VERSION 5.7 ;
BUSBITCHARS "[]" ;
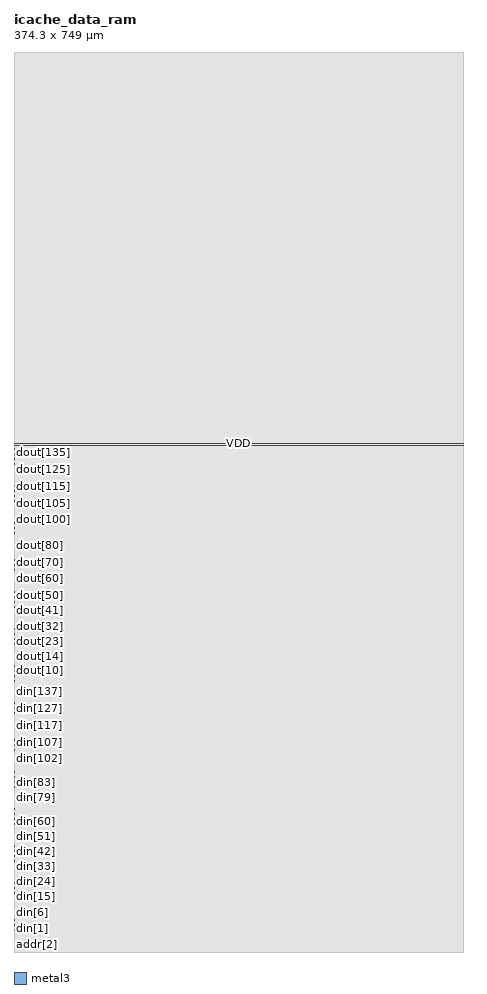
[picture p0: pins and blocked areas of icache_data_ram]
MACRO icache_data_ram
  FOREIGN icache_data_ram 0 0 ;
  SYMMETRY X Y R90 ;
  SIZE 374.300 BY 749.000 ;
  CLASS BLOCK ;
  PIN clk
    DIRECTION INPUT ;
    USE SIGNAL ;
    SHAPE ABUTMENT ;
    PORT
      LAYER metal3 ;
      RECT 0.000 1.400 0.140 1.540 ;
    END
  END clk
  PIN ce
    DIRECTION INPUT ;
    USE SIGNAL ;
    SHAPE ABUTMENT ;
    PORT
      LAYER metal3 ;
      RECT 0.000 2.800 0.140 2.940 ;
    END
  END ce
  PIN we
    DIRECTION INPUT ;
    USE SIGNAL ;
    SHAPE ABUTMENT ;
    PORT
      LAYER metal3 ;
      RECT 0.000 4.200 0.140 4.340 ;
    END
  END we
  PIN addr[0]
    DIRECTION INPUT ;
    USE SIGNAL ;
    SHAPE ABUTMENT ;
    PORT
      LAYER metal3 ;
      RECT 0.000 5.600 0.140 5.740 ;
    END
  END addr[0]
  PIN addr[1]
    DIRECTION INPUT ;
    USE SIGNAL ;
    SHAPE ABUTMENT ;
    PORT
      LAYER metal3 ;
      RECT 0.000 7.000 0.140 7.140 ;
    END
  END addr[1]
  PIN addr[2]
    DIRECTION INPUT ;
    USE SIGNAL ;
    SHAPE ABUTMENT ;
    PORT
      LAYER metal3 ;
      RECT 0.000 8.400 0.140 8.540 ;
    END
  END addr[2]
  PIN addr[3]
    DIRECTION INPUT ;
    USE SIGNAL ;
    SHAPE ABUTMENT ;
    PORT
      LAYER metal3 ;
      RECT 0.000 9.800 0.140 9.940 ;
    END
  END addr[3]
  PIN addr[4]
    DIRECTION INPUT ;
    USE SIGNAL ;
    SHAPE ABUTMENT ;
    PORT
      LAYER metal3 ;
      RECT 0.000 11.200 0.140 11.340 ;
    END
  END addr[4]
  PIN addr[5]
    DIRECTION INPUT ;
    USE SIGNAL ;
    SHAPE ABUTMENT ;
    PORT
      LAYER metal3 ;
      RECT 0.000 12.600 0.140 12.740 ;
    END
  END addr[5]
  PIN addr[6]
    DIRECTION INPUT ;
    USE SIGNAL ;
    SHAPE ABUTMENT ;
    PORT
      LAYER metal3 ;
      RECT 0.000 14.000 0.140 14.140 ;
    END
  END addr[6]
  PIN addr[7]
    DIRECTION INPUT ;
    USE SIGNAL ;
    SHAPE ABUTMENT ;
    PORT
      LAYER metal3 ;
      RECT 0.000 15.400 0.140 15.540 ;
    END
  END addr[7]
  PIN addr[8]
    DIRECTION INPUT ;
    USE SIGNAL ;
    SHAPE ABUTMENT ;
    PORT
      LAYER metal3 ;
      RECT 0.000 16.800 0.140 16.940 ;
    END
  END addr[8]
  PIN din[0]
    DIRECTION INPUT ;
    USE SIGNAL ;
    SHAPE ABUTMENT ;
    PORT
      LAYER metal3 ;
      RECT 0.000 18.200 0.140 18.340 ;
    END
  END din[0]
  PIN din[1]
    DIRECTION INPUT ;
    USE SIGNAL ;
    SHAPE ABUTMENT ;
    PORT
      LAYER metal3 ;
      RECT 0.000 19.600 0.140 19.740 ;
    END
  END din[1]
  PIN din[2]
    DIRECTION INPUT ;
    USE SIGNAL ;
    SHAPE ABUTMENT ;
    PORT
      LAYER metal3 ;
      RECT 0.000 21.000 0.140 21.140 ;
    END
  END din[2]
  PIN din[3]
    DIRECTION INPUT ;
    USE SIGNAL ;
    SHAPE ABUTMENT ;
    PORT
      LAYER metal3 ;
      RECT 0.000 22.400 0.140 22.540 ;
    END
  END din[3]
  PIN din[4]
    DIRECTION INPUT ;
    USE SIGNAL ;
    SHAPE ABUTMENT ;
    PORT
      LAYER metal3 ;
      RECT 0.000 23.800 0.140 23.940 ;
    END
  END din[4]
  PIN din[5]
    DIRECTION INPUT ;
    USE SIGNAL ;
    SHAPE ABUTMENT ;
    PORT
      LAYER metal3 ;
      RECT 0.000 25.200 0.140 25.340 ;
    END
  END din[5]
  PIN din[6]
    DIRECTION INPUT ;
    USE SIGNAL ;
    SHAPE ABUTMENT ;
    PORT
      LAYER metal3 ;
      RECT 0.000 26.600 0.140 26.740 ;
    END
  END din[6]
  PIN din[7]
    DIRECTION INPUT ;
    USE SIGNAL ;
    SHAPE ABUTMENT ;
    PORT
      LAYER metal3 ;
      RECT 0.000 28.000 0.140 28.140 ;
    END
  END din[7]
  PIN din[8]
    DIRECTION INPUT ;
    USE SIGNAL ;
    SHAPE ABUTMENT ;
    PORT
      LAYER metal3 ;
      RECT 0.000 29.400 0.140 29.540 ;
    END
  END din[8]
  PIN din[9]
    DIRECTION INPUT ;
    USE SIGNAL ;
    SHAPE ABUTMENT ;
    PORT
      LAYER metal3 ;
      RECT 0.000 30.800 0.140 30.940 ;
    END
  END din[9]
  PIN din[10]
    DIRECTION INPUT ;
    USE SIGNAL ;
    SHAPE ABUTMENT ;
    PORT
      LAYER metal3 ;
      RECT 0.000 32.200 0.140 32.340 ;
    END
  END din[10]
  PIN din[11]
    DIRECTION INPUT ;
    USE SIGNAL ;
    SHAPE ABUTMENT ;
    PORT
      LAYER metal3 ;
      RECT 0.000 33.600 0.140 33.740 ;
    END
  END din[11]
  PIN din[12]
    DIRECTION INPUT ;
    USE SIGNAL ;
    SHAPE ABUTMENT ;
    PORT
      LAYER metal3 ;
      RECT 0.000 35.000 0.140 35.140 ;
    END
  END din[12]
  PIN din[13]
    DIRECTION INPUT ;
    USE SIGNAL ;
    SHAPE ABUTMENT ;
    PORT
      LAYER metal3 ;
      RECT 0.000 36.400 0.140 36.540 ;
    END
  END din[13]
  PIN din[14]
    DIRECTION INPUT ;
    USE SIGNAL ;
    SHAPE ABUTMENT ;
    PORT
      LAYER metal3 ;
      RECT 0.000 37.800 0.140 37.940 ;
    END
  END din[14]
  PIN din[15]
    DIRECTION INPUT ;
    USE SIGNAL ;
    SHAPE ABUTMENT ;
    PORT
      LAYER metal3 ;
      RECT 0.000 39.200 0.140 39.340 ;
    END
  END din[15]
  PIN din[16]
    DIRECTION INPUT ;
    USE SIGNAL ;
    SHAPE ABUTMENT ;
    PORT
      LAYER metal3 ;
      RECT 0.000 40.600 0.140 40.740 ;
    END
  END din[16]
  PIN din[17]
    DIRECTION INPUT ;
    USE SIGNAL ;
    SHAPE ABUTMENT ;
    PORT
      LAYER metal3 ;
      RECT 0.000 42.000 0.140 42.140 ;
    END
  END din[17]
  PIN din[18]
    DIRECTION INPUT ;
    USE SIGNAL ;
    SHAPE ABUTMENT ;
    PORT
      LAYER metal3 ;
      RECT 0.000 43.400 0.140 43.540 ;
    END
  END din[18]
  PIN din[19]
    DIRECTION INPUT ;
    USE SIGNAL ;
    SHAPE ABUTMENT ;
    PORT
      LAYER metal3 ;
      RECT 0.000 44.800 0.140 44.940 ;
    END
  END din[19]
  PIN din[20]
    DIRECTION INPUT ;
    USE SIGNAL ;
    SHAPE ABUTMENT ;
    PORT
      LAYER metal3 ;
      RECT 0.000 46.200 0.140 46.340 ;
    END
  END din[20]
  PIN din[21]
    DIRECTION INPUT ;
    USE SIGNAL ;
    SHAPE ABUTMENT ;
    PORT
      LAYER metal3 ;
      RECT 0.000 47.600 0.140 47.740 ;
    END
  END din[21]
  PIN din[22]
    DIRECTION INPUT ;
    USE SIGNAL ;
    SHAPE ABUTMENT ;
    PORT
      LAYER metal3 ;
      RECT 0.000 49.000 0.140 49.140 ;
    END
  END din[22]
  PIN din[23]
    DIRECTION INPUT ;
    USE SIGNAL ;
    SHAPE ABUTMENT ;
    PORT
      LAYER metal3 ;
      RECT 0.000 50.400 0.140 50.540 ;
    END
  END din[23]
  PIN din[24]
    DIRECTION INPUT ;
    USE SIGNAL ;
    SHAPE ABUTMENT ;
    PORT
      LAYER metal3 ;
      RECT 0.000 51.800 0.140 51.940 ;
    END
  END din[24]
  PIN din[25]
    DIRECTION INPUT ;
    USE SIGNAL ;
    SHAPE ABUTMENT ;
    PORT
      LAYER metal3 ;
      RECT 0.000 53.200 0.140 53.340 ;
    END
  END din[25]
  PIN din[26]
    DIRECTION INPUT ;
    USE SIGNAL ;
    SHAPE ABUTMENT ;
    PORT
      LAYER metal3 ;
      RECT 0.000 54.600 0.140 54.740 ;
    END
  END din[26]
  PIN din[27]
    DIRECTION INPUT ;
    USE SIGNAL ;
    SHAPE ABUTMENT ;
    PORT
      LAYER metal3 ;
      RECT 0.000 56.000 0.140 56.140 ;
    END
  END din[27]
  PIN din[28]
    DIRECTION INPUT ;
    USE SIGNAL ;
    SHAPE ABUTMENT ;
    PORT
      LAYER metal3 ;
      RECT 0.000 57.400 0.140 57.540 ;
    END
  END din[28]
  PIN din[29]
    DIRECTION INPUT ;
    USE SIGNAL ;
    SHAPE ABUTMENT ;
    PORT
      LAYER metal3 ;
      RECT 0.000 58.800 0.140 58.940 ;
    END
  END din[29]
  PIN din[30]
    DIRECTION INPUT ;
    USE SIGNAL ;
    SHAPE ABUTMENT ;
    PORT
      LAYER metal3 ;
      RECT 0.000 60.200 0.140 60.340 ;
    END
  END din[30]
  PIN din[31]
    DIRECTION INPUT ;
    USE SIGNAL ;
    SHAPE ABUTMENT ;
    PORT
      LAYER metal3 ;
      RECT 0.000 61.600 0.140 61.740 ;
    END
  END din[31]
  PIN din[32]
    DIRECTION INPUT ;
    USE SIGNAL ;
    SHAPE ABUTMENT ;
    PORT
      LAYER metal3 ;
      RECT 0.000 63.000 0.140 63.140 ;
    END
  END din[32]
  PIN din[33]
    DIRECTION INPUT ;
    USE SIGNAL ;
    SHAPE ABUTMENT ;
    PORT
      LAYER metal3 ;
      RECT 0.000 64.400 0.140 64.540 ;
    END
  END din[33]
  PIN din[34]
    DIRECTION INPUT ;
    USE SIGNAL ;
    SHAPE ABUTMENT ;
    PORT
      LAYER metal3 ;
      RECT 0.000 65.800 0.140 65.940 ;
    END
  END din[34]
  PIN din[35]
    DIRECTION INPUT ;
    USE SIGNAL ;
    SHAPE ABUTMENT ;
    PORT
      LAYER metal3 ;
      RECT 0.000 67.200 0.140 67.340 ;
    END
  END din[35]
  PIN din[36]
    DIRECTION INPUT ;
    USE SIGNAL ;
    SHAPE ABUTMENT ;
    PORT
      LAYER metal3 ;
      RECT 0.000 68.600 0.140 68.740 ;
    END
  END din[36]
  PIN din[37]
    DIRECTION INPUT ;
    USE SIGNAL ;
    SHAPE ABUTMENT ;
    PORT
      LAYER metal3 ;
      RECT 0.000 70.000 0.140 70.140 ;
    END
  END din[37]
  PIN din[38]
    DIRECTION INPUT ;
    USE SIGNAL ;
    SHAPE ABUTMENT ;
    PORT
      LAYER metal3 ;
      RECT 0.000 71.400 0.140 71.540 ;
    END
  END din[38]
  PIN din[39]
    DIRECTION INPUT ;
    USE SIGNAL ;
    SHAPE ABUTMENT ;
    PORT
      LAYER metal3 ;
      RECT 0.000 72.800 0.140 72.940 ;
    END
  END din[39]
  PIN din[40]
    DIRECTION INPUT ;
    USE SIGNAL ;
    SHAPE ABUTMENT ;
    PORT
      LAYER metal3 ;
      RECT 0.000 74.200 0.140 74.340 ;
    END
  END din[40]
  PIN din[41]
    DIRECTION INPUT ;
    USE SIGNAL ;
    SHAPE ABUTMENT ;
    PORT
      LAYER metal3 ;
      RECT 0.000 75.600 0.140 75.740 ;
    END
  END din[41]
  PIN din[42]
    DIRECTION INPUT ;
    USE SIGNAL ;
    SHAPE ABUTMENT ;
    PORT
      LAYER metal3 ;
      RECT 0.000 77.000 0.140 77.140 ;
    END
  END din[42]
  PIN din[43]
    DIRECTION INPUT ;
    USE SIGNAL ;
    SHAPE ABUTMENT ;
    PORT
      LAYER metal3 ;
      RECT 0.000 78.400 0.140 78.540 ;
    END
  END din[43]
  PIN din[44]
    DIRECTION INPUT ;
    USE SIGNAL ;
    SHAPE ABUTMENT ;
    PORT
      LAYER metal3 ;
      RECT 0.000 79.800 0.140 79.940 ;
    END
  END din[44]
  PIN din[45]
    DIRECTION INPUT ;
    USE SIGNAL ;
    SHAPE ABUTMENT ;
    PORT
      LAYER metal3 ;
      RECT 0.000 81.200 0.140 81.340 ;
    END
  END din[45]
  PIN din[46]
    DIRECTION INPUT ;
    USE SIGNAL ;
    SHAPE ABUTMENT ;
    PORT
      LAYER metal3 ;
      RECT 0.000 82.600 0.140 82.740 ;
    END
  END din[46]
  PIN din[47]
    DIRECTION INPUT ;
    USE SIGNAL ;
    SHAPE ABUTMENT ;
    PORT
      LAYER metal3 ;
      RECT 0.000 84.000 0.140 84.140 ;
    END
  END din[47]
  PIN din[48]
    DIRECTION INPUT ;
    USE SIGNAL ;
    SHAPE ABUTMENT ;
    PORT
      LAYER metal3 ;
      RECT 0.000 85.400 0.140 85.540 ;
    END
  END din[48]
  PIN din[49]
    DIRECTION INPUT ;
    USE SIGNAL ;
    SHAPE ABUTMENT ;
    PORT
      LAYER metal3 ;
      RECT 0.000 86.800 0.140 86.940 ;
    END
  END din[49]
  PIN din[50]
    DIRECTION INPUT ;
    USE SIGNAL ;
    SHAPE ABUTMENT ;
    PORT
      LAYER metal3 ;
      RECT 0.000 88.200 0.140 88.340 ;
    END
  END din[50]
  PIN din[51]
    DIRECTION INPUT ;
    USE SIGNAL ;
    SHAPE ABUTMENT ;
    PORT
      LAYER metal3 ;
      RECT 0.000 89.600 0.140 89.740 ;
    END
  END din[51]
  PIN din[52]
    DIRECTION INPUT ;
    USE SIGNAL ;
    SHAPE ABUTMENT ;
    PORT
      LAYER metal3 ;
      RECT 0.000 91.000 0.140 91.140 ;
    END
  END din[52]
  PIN din[53]
    DIRECTION INPUT ;
    USE SIGNAL ;
    SHAPE ABUTMENT ;
    PORT
      LAYER metal3 ;
      RECT 0.000 92.400 0.140 92.540 ;
    END
  END din[53]
  PIN din[54]
    DIRECTION INPUT ;
    USE SIGNAL ;
    SHAPE ABUTMENT ;
    PORT
      LAYER metal3 ;
      RECT 0.000 93.800 0.140 93.940 ;
    END
  END din[54]
  PIN din[55]
    DIRECTION INPUT ;
    USE SIGNAL ;
    SHAPE ABUTMENT ;
    PORT
      LAYER metal3 ;
      RECT 0.000 95.200 0.140 95.340 ;
    END
  END din[55]
  PIN din[56]
    DIRECTION INPUT ;
    USE SIGNAL ;
    SHAPE ABUTMENT ;
    PORT
      LAYER metal3 ;
      RECT 0.000 96.600 0.140 96.740 ;
    END
  END din[56]
  PIN din[57]
    DIRECTION INPUT ;
    USE SIGNAL ;
    SHAPE ABUTMENT ;
    PORT
      LAYER metal3 ;
      RECT 0.000 98.000 0.140 98.140 ;
    END
  END din[57]
  PIN din[58]
    DIRECTION INPUT ;
    USE SIGNAL ;
    SHAPE ABUTMENT ;
    PORT
      LAYER metal3 ;
      RECT 0.000 99.400 0.140 99.540 ;
    END
  END din[58]
  PIN din[59]
    DIRECTION INPUT ;
    USE SIGNAL ;
    SHAPE ABUTMENT ;
    PORT
      LAYER metal3 ;
      RECT 0.000 100.800 0.140 100.940 ;
    END
  END din[59]
  PIN din[60]
    DIRECTION INPUT ;
    USE SIGNAL ;
    SHAPE ABUTMENT ;
    PORT
      LAYER metal3 ;
      RECT 0.000 102.200 0.140 102.340 ;
    END
  END din[60]
  PIN din[61]
    DIRECTION INPUT ;
    USE SIGNAL ;
    SHAPE ABUTMENT ;
    PORT
      LAYER metal3 ;
      RECT 0.000 103.600 0.140 103.740 ;
    END
  END din[61]
  PIN din[62]
    DIRECTION INPUT ;
    USE SIGNAL ;
    SHAPE ABUTMENT ;
    PORT
      LAYER metal3 ;
      RECT 0.000 105.000 0.140 105.140 ;
    END
  END din[62]
  PIN din[63]
    DIRECTION INPUT ;
    USE SIGNAL ;
    SHAPE ABUTMENT ;
    PORT
      LAYER metal3 ;
      RECT 0.000 106.400 0.140 106.540 ;
    END
  END din[63]
  PIN din[64]
    DIRECTION INPUT ;
    USE SIGNAL ;
    SHAPE ABUTMENT ;
    PORT
      LAYER metal3 ;
      RECT 0.000 107.800 0.140 107.940 ;
    END
  END din[64]
  PIN din[65]
    DIRECTION INPUT ;
    USE SIGNAL ;
    SHAPE ABUTMENT ;
    PORT
      LAYER metal3 ;
      RECT 0.000 109.200 0.140 109.340 ;
    END
  END din[65]
  PIN din[66]
    DIRECTION INPUT ;
    USE SIGNAL ;
    SHAPE ABUTMENT ;
    PORT
      LAYER metal3 ;
      RECT 0.000 110.600 0.140 110.740 ;
    END
  END din[66]
  PIN din[67]
    DIRECTION INPUT ;
    USE SIGNAL ;
    SHAPE ABUTMENT ;
    PORT
      LAYER metal3 ;
      RECT 0.000 112.000 0.140 112.140 ;
    END
  END din[67]
  PIN din[68]
    DIRECTION INPUT ;
    USE SIGNAL ;
    SHAPE ABUTMENT ;
    PORT
      LAYER metal3 ;
      RECT 0.000 113.400 0.140 113.540 ;
    END
  END din[68]
  PIN din[69]
    DIRECTION INPUT ;
    USE SIGNAL ;
    SHAPE ABUTMENT ;
    PORT
      LAYER metal3 ;
      RECT 0.000 114.800 0.140 114.940 ;
    END
  END din[69]
  PIN din[70]
    DIRECTION INPUT ;
    USE SIGNAL ;
    SHAPE ABUTMENT ;
    PORT
      LAYER metal3 ;
      RECT 0.000 116.200 0.140 116.340 ;
    END
  END din[70]
  PIN din[71]
    DIRECTION INPUT ;
    USE SIGNAL ;
    SHAPE ABUTMENT ;
    PORT
      LAYER metal3 ;
      RECT 0.000 117.600 0.140 117.740 ;
    END
  END din[71]
  PIN din[72]
    DIRECTION INPUT ;
    USE SIGNAL ;
    SHAPE ABUTMENT ;
    PORT
      LAYER metal3 ;
      RECT 0.000 119.000 0.140 119.140 ;
    END
  END din[72]
  PIN din[73]
    DIRECTION INPUT ;
    USE SIGNAL ;
    SHAPE ABUTMENT ;
    PORT
      LAYER metal3 ;
      RECT 0.000 120.400 0.140 120.540 ;
    END
  END din[73]
  PIN din[74]
    DIRECTION INPUT ;
    USE SIGNAL ;
    SHAPE ABUTMENT ;
    PORT
      LAYER metal3 ;
      RECT 0.000 121.800 0.140 121.940 ;
    END
  END din[74]
  PIN din[75]
    DIRECTION INPUT ;
    USE SIGNAL ;
    SHAPE ABUTMENT ;
    PORT
      LAYER metal3 ;
      RECT 0.000 123.200 0.140 123.340 ;
    END
  END din[75]
  PIN din[76]
    DIRECTION INPUT ;
    USE SIGNAL ;
    SHAPE ABUTMENT ;
    PORT
      LAYER metal3 ;
      RECT 0.000 124.600 0.140 124.740 ;
    END
  END din[76]
  PIN din[77]
    DIRECTION INPUT ;
    USE SIGNAL ;
    SHAPE ABUTMENT ;
    PORT
      LAYER metal3 ;
      RECT 0.000 126.000 0.140 126.140 ;
    END
  END din[77]
  PIN din[78]
    DIRECTION INPUT ;
    USE SIGNAL ;
    SHAPE ABUTMENT ;
    PORT
      LAYER metal3 ;
      RECT 0.000 127.400 0.140 127.540 ;
    END
  END din[78]
  PIN din[79]
    DIRECTION INPUT ;
    USE SIGNAL ;
    SHAPE ABUTMENT ;
    PORT
      LAYER metal3 ;
      RECT 0.000 128.800 0.140 128.940 ;
    END
  END din[79]
  PIN din[80]
    DIRECTION INPUT ;
    USE SIGNAL ;
    SHAPE ABUTMENT ;
    PORT
      LAYER metal3 ;
      RECT 0.000 130.200 0.140 130.340 ;
    END
  END din[80]
  PIN din[81]
    DIRECTION INPUT ;
    USE SIGNAL ;
    SHAPE ABUTMENT ;
    PORT
      LAYER metal3 ;
      RECT 0.000 131.600 0.140 131.740 ;
    END
  END din[81]
  PIN din[82]
    DIRECTION INPUT ;
    USE SIGNAL ;
    SHAPE ABUTMENT ;
    PORT
      LAYER metal3 ;
      RECT 0.000 133.000 0.140 133.140 ;
    END
  END din[82]
  PIN din[83]
    DIRECTION INPUT ;
    USE SIGNAL ;
    SHAPE ABUTMENT ;
    PORT
      LAYER metal3 ;
      RECT 0.000 134.400 0.140 134.540 ;
    END
  END din[83]
  PIN din[84]
    DIRECTION INPUT ;
    USE SIGNAL ;
    SHAPE ABUTMENT ;
    PORT
      LAYER metal3 ;
      RECT 0.000 135.800 0.140 135.940 ;
    END
  END din[84]
  PIN din[85]
    DIRECTION INPUT ;
    USE SIGNAL ;
    SHAPE ABUTMENT ;
    PORT
      LAYER metal3 ;
      RECT 0.000 137.200 0.140 137.340 ;
    END
  END din[85]
  PIN din[86]
    DIRECTION INPUT ;
    USE SIGNAL ;
    SHAPE ABUTMENT ;
    PORT
      LAYER metal3 ;
      RECT 0.000 138.600 0.140 138.740 ;
    END
  END din[86]
  PIN din[87]
    DIRECTION INPUT ;
    USE SIGNAL ;
    SHAPE ABUTMENT ;
    PORT
      LAYER metal3 ;
      RECT 0.000 140.000 0.140 140.140 ;
    END
  END din[87]
  PIN din[88]
    DIRECTION INPUT ;
    USE SIGNAL ;
    SHAPE ABUTMENT ;
    PORT
      LAYER metal3 ;
      RECT 0.000 141.400 0.140 141.540 ;
    END
  END din[88]
  PIN din[89]
    DIRECTION INPUT ;
    USE SIGNAL ;
    SHAPE ABUTMENT ;
    PORT
      LAYER metal3 ;
      RECT 0.000 142.800 0.140 142.940 ;
    END
  END din[89]
  PIN din[90]
    DIRECTION INPUT ;
    USE SIGNAL ;
    SHAPE ABUTMENT ;
    PORT
      LAYER metal3 ;
      RECT 0.000 144.200 0.140 144.340 ;
    END
  END din[90]
  PIN din[91]
    DIRECTION INPUT ;
    USE SIGNAL ;
    SHAPE ABUTMENT ;
    PORT
      LAYER metal3 ;
      RECT 0.000 145.600 0.140 145.740 ;
    END
  END din[91]
  PIN din[92]
    DIRECTION INPUT ;
    USE SIGNAL ;
    SHAPE ABUTMENT ;
    PORT
      LAYER metal3 ;
      RECT 0.000 147.000 0.140 147.140 ;
    END
  END din[92]
  PIN din[93]
    DIRECTION INPUT ;
    USE SIGNAL ;
    SHAPE ABUTMENT ;
    PORT
      LAYER metal3 ;
      RECT 0.000 148.400 0.140 148.540 ;
    END
  END din[93]
  PIN din[94]
    DIRECTION INPUT ;
    USE SIGNAL ;
    SHAPE ABUTMENT ;
    PORT
      LAYER metal3 ;
      RECT 0.000 149.800 0.140 149.940 ;
    END
  END din[94]
  PIN din[95]
    DIRECTION INPUT ;
    USE SIGNAL ;
    SHAPE ABUTMENT ;
    PORT
      LAYER metal3 ;
      RECT 0.000 151.200 0.140 151.340 ;
    END
  END din[95]
  PIN din[96]
    DIRECTION INPUT ;
    USE SIGNAL ;
    SHAPE ABUTMENT ;
    PORT
      LAYER metal3 ;
      RECT 0.000 152.600 0.140 152.740 ;
    END
  END din[96]
  PIN din[97]
    DIRECTION INPUT ;
    USE SIGNAL ;
    SHAPE ABUTMENT ;
    PORT
      LAYER metal3 ;
      RECT 0.000 154.000 0.140 154.140 ;
    END
  END din[97]
  PIN din[98]
    DIRECTION INPUT ;
    USE SIGNAL ;
    SHAPE ABUTMENT ;
    PORT
      LAYER metal3 ;
      RECT 0.000 155.400 0.140 155.540 ;
    END
  END din[98]
  PIN din[99]
    DIRECTION INPUT ;
    USE SIGNAL ;
    SHAPE ABUTMENT ;
    PORT
      LAYER metal3 ;
      RECT 0.000 156.800 0.140 156.940 ;
    END
  END din[99]
  PIN din[100]
    DIRECTION INPUT ;
    USE SIGNAL ;
    SHAPE ABUTMENT ;
    PORT
      LAYER metal3 ;
      RECT 0.000 158.200 0.140 158.340 ;
    END
  END din[100]
  PIN din[101]
    DIRECTION INPUT ;
    USE SIGNAL ;
    SHAPE ABUTMENT ;
    PORT
      LAYER metal3 ;
      RECT 0.000 159.600 0.140 159.740 ;
    END
  END din[101]
  PIN din[102]
    DIRECTION INPUT ;
    USE SIGNAL ;
    SHAPE ABUTMENT ;
    PORT
      LAYER metal3 ;
      RECT 0.000 161.000 0.140 161.140 ;
    END
  END din[102]
  PIN din[103]
    DIRECTION INPUT ;
    USE SIGNAL ;
    SHAPE ABUTMENT ;
    PORT
      LAYER metal3 ;
      RECT 0.000 162.400 0.140 162.540 ;
    END
  END din[103]
  PIN din[104]
    DIRECTION INPUT ;
    USE SIGNAL ;
    SHAPE ABUTMENT ;
    PORT
      LAYER metal3 ;
      RECT 0.000 163.800 0.140 163.940 ;
    END
  END din[104]
  PIN din[105]
    DIRECTION INPUT ;
    USE SIGNAL ;
    SHAPE ABUTMENT ;
    PORT
      LAYER metal3 ;
      RECT 0.000 165.200 0.140 165.340 ;
    END
  END din[105]
  PIN din[106]
    DIRECTION INPUT ;
    USE SIGNAL ;
    SHAPE ABUTMENT ;
    PORT
      LAYER metal3 ;
      RECT 0.000 166.600 0.140 166.740 ;
    END
  END din[106]
  PIN din[107]
    DIRECTION INPUT ;
    USE SIGNAL ;
    SHAPE ABUTMENT ;
    PORT
      LAYER metal3 ;
      RECT 0.000 168.000 0.140 168.140 ;
    END
  END din[107]
  PIN din[108]
    DIRECTION INPUT ;
    USE SIGNAL ;
    SHAPE ABUTMENT ;
    PORT
      LAYER metal3 ;
      RECT 0.000 169.400 0.140 169.540 ;
    END
  END din[108]
  PIN din[109]
    DIRECTION INPUT ;
    USE SIGNAL ;
    SHAPE ABUTMENT ;
    PORT
      LAYER metal3 ;
      RECT 0.000 170.800 0.140 170.940 ;
    END
  END din[109]
  PIN din[110]
    DIRECTION INPUT ;
    USE SIGNAL ;
    SHAPE ABUTMENT ;
    PORT
      LAYER metal3 ;
      RECT 0.000 172.200 0.140 172.340 ;
    END
  END din[110]
  PIN din[111]
    DIRECTION INPUT ;
    USE SIGNAL ;
    SHAPE ABUTMENT ;
    PORT
      LAYER metal3 ;
      RECT 0.000 173.600 0.140 173.740 ;
    END
  END din[111]
  PIN din[112]
    DIRECTION INPUT ;
    USE SIGNAL ;
    SHAPE ABUTMENT ;
    PORT
      LAYER metal3 ;
      RECT 0.000 175.000 0.140 175.140 ;
    END
  END din[112]
  PIN din[113]
    DIRECTION INPUT ;
    USE SIGNAL ;
    SHAPE ABUTMENT ;
    PORT
      LAYER metal3 ;
      RECT 0.000 176.400 0.140 176.540 ;
    END
  END din[113]
  PIN din[114]
    DIRECTION INPUT ;
    USE SIGNAL ;
    SHAPE ABUTMENT ;
    PORT
      LAYER metal3 ;
      RECT 0.000 177.800 0.140 177.940 ;
    END
  END din[114]
  PIN din[115]
    DIRECTION INPUT ;
    USE SIGNAL ;
    SHAPE ABUTMENT ;
    PORT
      LAYER metal3 ;
      RECT 0.000 179.200 0.140 179.340 ;
    END
  END din[115]
  PIN din[116]
    DIRECTION INPUT ;
    USE SIGNAL ;
    SHAPE ABUTMENT ;
    PORT
      LAYER metal3 ;
      RECT 0.000 180.600 0.140 180.740 ;
    END
  END din[116]
  PIN din[117]
    DIRECTION INPUT ;
    USE SIGNAL ;
    SHAPE ABUTMENT ;
    PORT
      LAYER metal3 ;
      RECT 0.000 182.000 0.140 182.140 ;
    END
  END din[117]
  PIN din[118]
    DIRECTION INPUT ;
    USE SIGNAL ;
    SHAPE ABUTMENT ;
    PORT
      LAYER metal3 ;
      RECT 0.000 183.400 0.140 183.540 ;
    END
  END din[118]
  PIN din[119]
    DIRECTION INPUT ;
    USE SIGNAL ;
    SHAPE ABUTMENT ;
    PORT
      LAYER metal3 ;
      RECT 0.000 184.800 0.140 184.940 ;
    END
  END din[119]
  PIN din[120]
    DIRECTION INPUT ;
    USE SIGNAL ;
    SHAPE ABUTMENT ;
    PORT
      LAYER metal3 ;
      RECT 0.000 186.200 0.140 186.340 ;
    END
  END din[120]
  PIN din[121]
    DIRECTION INPUT ;
    USE SIGNAL ;
    SHAPE ABUTMENT ;
    PORT
      LAYER metal3 ;
      RECT 0.000 187.600 0.140 187.740 ;
    END
  END din[121]
  PIN din[122]
    DIRECTION INPUT ;
    USE SIGNAL ;
    SHAPE ABUTMENT ;
    PORT
      LAYER metal3 ;
      RECT 0.000 189.000 0.140 189.140 ;
    END
  END din[122]
  PIN din[123]
    DIRECTION INPUT ;
    USE SIGNAL ;
    SHAPE ABUTMENT ;
    PORT
      LAYER metal3 ;
      RECT 0.000 190.400 0.140 190.540 ;
    END
  END din[123]
  PIN din[124]
    DIRECTION INPUT ;
    USE SIGNAL ;
    SHAPE ABUTMENT ;
    PORT
      LAYER metal3 ;
      RECT 0.000 191.800 0.140 191.940 ;
    END
  END din[124]
  PIN din[125]
    DIRECTION INPUT ;
    USE SIGNAL ;
    SHAPE ABUTMENT ;
    PORT
      LAYER metal3 ;
      RECT 0.000 193.200 0.140 193.340 ;
    END
  END din[125]
  PIN din[126]
    DIRECTION INPUT ;
    USE SIGNAL ;
    SHAPE ABUTMENT ;
    PORT
      LAYER metal3 ;
      RECT 0.000 194.600 0.140 194.740 ;
    END
  END din[126]
  PIN din[127]
    DIRECTION INPUT ;
    USE SIGNAL ;
    SHAPE ABUTMENT ;
    PORT
      LAYER metal3 ;
      RECT 0.000 196.000 0.140 196.140 ;
    END
  END din[127]
  PIN din[128]
    DIRECTION INPUT ;
    USE SIGNAL ;
    SHAPE ABUTMENT ;
    PORT
      LAYER metal3 ;
      RECT 0.000 197.400 0.140 197.540 ;
    END
  END din[128]
  PIN din[129]
    DIRECTION INPUT ;
    USE SIGNAL ;
    SHAPE ABUTMENT ;
    PORT
      LAYER metal3 ;
      RECT 0.000 198.800 0.140 198.940 ;
    END
  END din[129]
  PIN din[130]
    DIRECTION INPUT ;
    USE SIGNAL ;
    SHAPE ABUTMENT ;
    PORT
      LAYER metal3 ;
      RECT 0.000 200.200 0.140 200.340 ;
    END
  END din[130]
  PIN din[131]
    DIRECTION INPUT ;
    USE SIGNAL ;
    SHAPE ABUTMENT ;
    PORT
      LAYER metal3 ;
      RECT 0.000 201.600 0.140 201.740 ;
    END
  END din[131]
  PIN din[132]
    DIRECTION INPUT ;
    USE SIGNAL ;
    SHAPE ABUTMENT ;
    PORT
      LAYER metal3 ;
      RECT 0.000 203.000 0.140 203.140 ;
    END
  END din[132]
  PIN din[133]
    DIRECTION INPUT ;
    USE SIGNAL ;
    SHAPE ABUTMENT ;
    PORT
      LAYER metal3 ;
      RECT 0.000 204.400 0.140 204.540 ;
    END
  END din[133]
  PIN din[134]
    DIRECTION INPUT ;
    USE SIGNAL ;
    SHAPE ABUTMENT ;
    PORT
      LAYER metal3 ;
      RECT 0.000 205.800 0.140 205.940 ;
    END
  END din[134]
  PIN din[135]
    DIRECTION INPUT ;
    USE SIGNAL ;
    SHAPE ABUTMENT ;
    PORT
      LAYER metal3 ;
      RECT 0.000 207.200 0.140 207.340 ;
    END
  END din[135]
  PIN din[136]
    DIRECTION INPUT ;
    USE SIGNAL ;
    SHAPE ABUTMENT ;
    PORT
      LAYER metal3 ;
      RECT 0.000 208.600 0.140 208.740 ;
    END
  END din[136]
  PIN din[137]
    DIRECTION INPUT ;
    USE SIGNAL ;
    SHAPE ABUTMENT ;
    PORT
      LAYER metal3 ;
      RECT 0.000 210.000 0.140 210.140 ;
    END
  END din[137]
  PIN din[138]
    DIRECTION INPUT ;
    USE SIGNAL ;
    SHAPE ABUTMENT ;
    PORT
      LAYER metal3 ;
      RECT 0.000 211.400 0.140 211.540 ;
    END
  END din[138]
  PIN din[139]
    DIRECTION INPUT ;
    USE SIGNAL ;
    SHAPE ABUTMENT ;
    PORT
      LAYER metal3 ;
      RECT 0.000 212.800 0.140 212.940 ;
    END
  END din[139]
  PIN din[140]
    DIRECTION INPUT ;
    USE SIGNAL ;
    SHAPE ABUTMENT ;
    PORT
      LAYER metal3 ;
      RECT 0.000 214.200 0.140 214.340 ;
    END
  END din[140]
  PIN din[141]
    DIRECTION INPUT ;
    USE SIGNAL ;
    SHAPE ABUTMENT ;
    PORT
      LAYER metal3 ;
      RECT 0.000 215.600 0.140 215.740 ;
    END
  END din[141]
  PIN din[142]
    DIRECTION INPUT ;
    USE SIGNAL ;
    SHAPE ABUTMENT ;
    PORT
      LAYER metal3 ;
      RECT 0.000 217.000 0.140 217.140 ;
    END
  END din[142]
  PIN din[143]
    DIRECTION INPUT ;
    USE SIGNAL ;
    SHAPE ABUTMENT ;
    PORT
      LAYER metal3 ;
      RECT 0.000 218.400 0.140 218.540 ;
    END
  END din[143]
  PIN dout[0]
    DIRECTION OUTPUT ;
    USE SIGNAL ;
    SHAPE ABUTMENT ;
    PORT
      LAYER metal3 ;
      RECT 0.000 219.800 0.140 219.940 ;
    END
  END dout[0]
  PIN dout[1]
    DIRECTION OUTPUT ;
    USE SIGNAL ;
    SHAPE ABUTMENT ;
    PORT
      LAYER metal3 ;
      RECT 0.000 221.200 0.140 221.340 ;
    END
  END dout[1]
  PIN dout[2]
    DIRECTION OUTPUT ;
    USE SIGNAL ;
    SHAPE ABUTMENT ;
    PORT
      LAYER metal3 ;
      RECT 0.000 222.600 0.140 222.740 ;
    END
  END dout[2]
  PIN dout[3]
    DIRECTION OUTPUT ;
    USE SIGNAL ;
    SHAPE ABUTMENT ;
    PORT
      LAYER metal3 ;
      RECT 0.000 224.000 0.140 224.140 ;
    END
  END dout[3]
  PIN dout[4]
    DIRECTION OUTPUT ;
    USE SIGNAL ;
    SHAPE ABUTMENT ;
    PORT
      LAYER metal3 ;
      RECT 0.000 225.400 0.140 225.540 ;
    END
  END dout[4]
  PIN dout[5]
    DIRECTION OUTPUT ;
    USE SIGNAL ;
    SHAPE ABUTMENT ;
    PORT
      LAYER metal3 ;
      RECT 0.000 226.800 0.140 226.940 ;
    END
  END dout[5]
  PIN dout[6]
    DIRECTION OUTPUT ;
    USE SIGNAL ;
    SHAPE ABUTMENT ;
    PORT
      LAYER metal3 ;
      RECT 0.000 228.200 0.140 228.340 ;
    END
  END dout[6]
  PIN dout[7]
    DIRECTION OUTPUT ;
    USE SIGNAL ;
    SHAPE ABUTMENT ;
    PORT
      LAYER metal3 ;
      RECT 0.000 229.600 0.140 229.740 ;
    END
  END dout[7]
  PIN dout[8]
    DIRECTION OUTPUT ;
    USE SIGNAL ;
    SHAPE ABUTMENT ;
    PORT
      LAYER metal3 ;
      RECT 0.000 231.000 0.140 231.140 ;
    END
  END dout[8]
  PIN dout[9]
    DIRECTION OUTPUT ;
    USE SIGNAL ;
    SHAPE ABUTMENT ;
    PORT
      LAYER metal3 ;
      RECT 0.000 232.400 0.140 232.540 ;
    END
  END dout[9]
  PIN dout[10]
    DIRECTION OUTPUT ;
    USE SIGNAL ;
    SHAPE ABUTMENT ;
    PORT
      LAYER metal3 ;
      RECT 0.000 233.800 0.140 233.940 ;
    END
  END dout[10]
  PIN dout[11]
    DIRECTION OUTPUT ;
    USE SIGNAL ;
    SHAPE ABUTMENT ;
    PORT
      LAYER metal3 ;
      RECT 0.000 235.200 0.140 235.340 ;
    END
  END dout[11]
  PIN dout[12]
    DIRECTION OUTPUT ;
    USE SIGNAL ;
    SHAPE ABUTMENT ;
    PORT
      LAYER metal3 ;
      RECT 0.000 236.600 0.140 236.740 ;
    END
  END dout[12]
  PIN dout[13]
    DIRECTION OUTPUT ;
    USE SIGNAL ;
    SHAPE ABUTMENT ;
    PORT
      LAYER metal3 ;
      RECT 0.000 238.000 0.140 238.140 ;
    END
  END dout[13]
  PIN dout[14]
    DIRECTION OUTPUT ;
    USE SIGNAL ;
    SHAPE ABUTMENT ;
    PORT
      LAYER metal3 ;
      RECT 0.000 239.400 0.140 239.540 ;
    END
  END dout[14]
  PIN dout[15]
    DIRECTION OUTPUT ;
    USE SIGNAL ;
    SHAPE ABUTMENT ;
    PORT
      LAYER metal3 ;
      RECT 0.000 240.800 0.140 240.940 ;
    END
  END dout[15]
  PIN dout[16]
    DIRECTION OUTPUT ;
    USE SIGNAL ;
    SHAPE ABUTMENT ;
    PORT
      LAYER metal3 ;
      RECT 0.000 242.200 0.140 242.340 ;
    END
  END dout[16]
  PIN dout[17]
    DIRECTION OUTPUT ;
    USE SIGNAL ;
    SHAPE ABUTMENT ;
    PORT
      LAYER metal3 ;
      RECT 0.000 243.600 0.140 243.740 ;
    END
  END dout[17]
  PIN dout[18]
    DIRECTION OUTPUT ;
    USE SIGNAL ;
    SHAPE ABUTMENT ;
    PORT
      LAYER metal3 ;
      RECT 0.000 245.000 0.140 245.140 ;
    END
  END dout[18]
  PIN dout[19]
    DIRECTION OUTPUT ;
    USE SIGNAL ;
    SHAPE ABUTMENT ;
    PORT
      LAYER metal3 ;
      RECT 0.000 246.400 0.140 246.540 ;
    END
  END dout[19]
  PIN dout[20]
    DIRECTION OUTPUT ;
    USE SIGNAL ;
    SHAPE ABUTMENT ;
    PORT
      LAYER metal3 ;
      RECT 0.000 247.800 0.140 247.940 ;
    END
  END dout[20]
  PIN dout[21]
    DIRECTION OUTPUT ;
    USE SIGNAL ;
    SHAPE ABUTMENT ;
    PORT
      LAYER metal3 ;
      RECT 0.000 249.200 0.140 249.340 ;
    END
  END dout[21]
  PIN dout[22]
    DIRECTION OUTPUT ;
    USE SIGNAL ;
    SHAPE ABUTMENT ;
    PORT
      LAYER metal3 ;
      RECT 0.000 250.600 0.140 250.740 ;
    END
  END dout[22]
  PIN dout[23]
    DIRECTION OUTPUT ;
    USE SIGNAL ;
    SHAPE ABUTMENT ;
    PORT
      LAYER metal3 ;
      RECT 0.000 252.000 0.140 252.140 ;
    END
  END dout[23]
  PIN dout[24]
    DIRECTION OUTPUT ;
    USE SIGNAL ;
    SHAPE ABUTMENT ;
    PORT
      LAYER metal3 ;
      RECT 0.000 253.400 0.140 253.540 ;
    END
  END dout[24]
  PIN dout[25]
    DIRECTION OUTPUT ;
    USE SIGNAL ;
    SHAPE ABUTMENT ;
    PORT
      LAYER metal3 ;
      RECT 0.000 254.800 0.140 254.940 ;
    END
  END dout[25]
  PIN dout[26]
    DIRECTION OUTPUT ;
    USE SIGNAL ;
    SHAPE ABUTMENT ;
    PORT
      LAYER metal3 ;
      RECT 0.000 256.200 0.140 256.340 ;
    END
  END dout[26]
  PIN dout[27]
    DIRECTION OUTPUT ;
    USE SIGNAL ;
    SHAPE ABUTMENT ;
    PORT
      LAYER metal3 ;
      RECT 0.000 257.600 0.140 257.740 ;
    END
  END dout[27]
  PIN dout[28]
    DIRECTION OUTPUT ;
    USE SIGNAL ;
    SHAPE ABUTMENT ;
    PORT
      LAYER metal3 ;
      RECT 0.000 259.000 0.140 259.140 ;
    END
  END dout[28]
  PIN dout[29]
    DIRECTION OUTPUT ;
    USE SIGNAL ;
    SHAPE ABUTMENT ;
    PORT
      LAYER metal3 ;
      RECT 0.000 260.400 0.140 260.540 ;
    END
  END dout[29]
  PIN dout[30]
    DIRECTION OUTPUT ;
    USE SIGNAL ;
    SHAPE ABUTMENT ;
    PORT
      LAYER metal3 ;
      RECT 0.000 261.800 0.140 261.940 ;
    END
  END dout[30]
  PIN dout[31]
    DIRECTION OUTPUT ;
    USE SIGNAL ;
    SHAPE ABUTMENT ;
    PORT
      LAYER metal3 ;
      RECT 0.000 263.200 0.140 263.340 ;
    END
  END dout[31]
  PIN dout[32]
    DIRECTION OUTPUT ;
    USE SIGNAL ;
    SHAPE ABUTMENT ;
    PORT
      LAYER metal3 ;
      RECT 0.000 264.600 0.140 264.740 ;
    END
  END dout[32]
  PIN dout[33]
    DIRECTION OUTPUT ;
    USE SIGNAL ;
    SHAPE ABUTMENT ;
    PORT
      LAYER metal3 ;
      RECT 0.000 266.000 0.140 266.140 ;
    END
  END dout[33]
  PIN dout[34]
    DIRECTION OUTPUT ;
    USE SIGNAL ;
    SHAPE ABUTMENT ;
    PORT
      LAYER metal3 ;
      RECT 0.000 267.400 0.140 267.540 ;
    END
  END dout[34]
  PIN dout[35]
    DIRECTION OUTPUT ;
    USE SIGNAL ;
    SHAPE ABUTMENT ;
    PORT
      LAYER metal3 ;
      RECT 0.000 268.800 0.140 268.940 ;
    END
  END dout[35]
  PIN dout[36]
    DIRECTION OUTPUT ;
    USE SIGNAL ;
    SHAPE ABUTMENT ;
    PORT
      LAYER metal3 ;
      RECT 0.000 270.200 0.140 270.340 ;
    END
  END dout[36]
  PIN dout[37]
    DIRECTION OUTPUT ;
    USE SIGNAL ;
    SHAPE ABUTMENT ;
    PORT
      LAYER metal3 ;
      RECT 0.000 271.600 0.140 271.740 ;
    END
  END dout[37]
  PIN dout[38]
    DIRECTION OUTPUT ;
    USE SIGNAL ;
    SHAPE ABUTMENT ;
    PORT
      LAYER metal3 ;
      RECT 0.000 273.000 0.140 273.140 ;
    END
  END dout[38]
  PIN dout[39]
    DIRECTION OUTPUT ;
    USE SIGNAL ;
    SHAPE ABUTMENT ;
    PORT
      LAYER metal3 ;
      RECT 0.000 274.400 0.140 274.540 ;
    END
  END dout[39]
  PIN dout[40]
    DIRECTION OUTPUT ;
    USE SIGNAL ;
    SHAPE ABUTMENT ;
    PORT
      LAYER metal3 ;
      RECT 0.000 275.800 0.140 275.940 ;
    END
  END dout[40]
  PIN dout[41]
    DIRECTION OUTPUT ;
    USE SIGNAL ;
    SHAPE ABUTMENT ;
    PORT
      LAYER metal3 ;
      RECT 0.000 277.200 0.140 277.340 ;
    END
  END dout[41]
  PIN dout[42]
    DIRECTION OUTPUT ;
    USE SIGNAL ;
    SHAPE ABUTMENT ;
    PORT
      LAYER metal3 ;
      RECT 0.000 278.600 0.140 278.740 ;
    END
  END dout[42]
  PIN dout[43]
    DIRECTION OUTPUT ;
    USE SIGNAL ;
    SHAPE ABUTMENT ;
    PORT
      LAYER metal3 ;
      RECT 0.000 280.000 0.140 280.140 ;
    END
  END dout[43]
  PIN dout[44]
    DIRECTION OUTPUT ;
    USE SIGNAL ;
    SHAPE ABUTMENT ;
    PORT
      LAYER metal3 ;
      RECT 0.000 281.400 0.140 281.540 ;
    END
  END dout[44]
  PIN dout[45]
    DIRECTION OUTPUT ;
    USE SIGNAL ;
    SHAPE ABUTMENT ;
    PORT
      LAYER metal3 ;
      RECT 0.000 282.800 0.140 282.940 ;
    END
  END dout[45]
  PIN dout[46]
    DIRECTION OUTPUT ;
    USE SIGNAL ;
    SHAPE ABUTMENT ;
    PORT
      LAYER metal3 ;
      RECT 0.000 284.200 0.140 284.340 ;
    END
  END dout[46]
  PIN dout[47]
    DIRECTION OUTPUT ;
    USE SIGNAL ;
    SHAPE ABUTMENT ;
    PORT
      LAYER metal3 ;
      RECT 0.000 285.600 0.140 285.740 ;
    END
  END dout[47]
  PIN dout[48]
    DIRECTION OUTPUT ;
    USE SIGNAL ;
    SHAPE ABUTMENT ;
    PORT
      LAYER metal3 ;
      RECT 0.000 287.000 0.140 287.140 ;
    END
  END dout[48]
  PIN dout[49]
    DIRECTION OUTPUT ;
    USE SIGNAL ;
    SHAPE ABUTMENT ;
    PORT
      LAYER metal3 ;
      RECT 0.000 288.400 0.140 288.540 ;
    END
  END dout[49]
  PIN dout[50]
    DIRECTION OUTPUT ;
    USE SIGNAL ;
    SHAPE ABUTMENT ;
    PORT
      LAYER metal3 ;
      RECT 0.000 289.800 0.140 289.940 ;
    END
  END dout[50]
  PIN dout[51]
    DIRECTION OUTPUT ;
    USE SIGNAL ;
    SHAPE ABUTMENT ;
    PORT
      LAYER metal3 ;
      RECT 0.000 291.200 0.140 291.340 ;
    END
  END dout[51]
  PIN dout[52]
    DIRECTION OUTPUT ;
    USE SIGNAL ;
    SHAPE ABUTMENT ;
    PORT
      LAYER metal3 ;
      RECT 0.000 292.600 0.140 292.740 ;
    END
  END dout[52]
  PIN dout[53]
    DIRECTION OUTPUT ;
    USE SIGNAL ;
    SHAPE ABUTMENT ;
    PORT
      LAYER metal3 ;
      RECT 0.000 294.000 0.140 294.140 ;
    END
  END dout[53]
  PIN dout[54]
    DIRECTION OUTPUT ;
    USE SIGNAL ;
    SHAPE ABUTMENT ;
    PORT
      LAYER metal3 ;
      RECT 0.000 295.400 0.140 295.540 ;
    END
  END dout[54]
  PIN dout[55]
    DIRECTION OUTPUT ;
    USE SIGNAL ;
    SHAPE ABUTMENT ;
    PORT
      LAYER metal3 ;
      RECT 0.000 296.800 0.140 296.940 ;
    END
  END dout[55]
  PIN dout[56]
    DIRECTION OUTPUT ;
    USE SIGNAL ;
    SHAPE ABUTMENT ;
    PORT
      LAYER metal3 ;
      RECT 0.000 298.200 0.140 298.340 ;
    END
  END dout[56]
  PIN dout[57]
    DIRECTION OUTPUT ;
    USE SIGNAL ;
    SHAPE ABUTMENT ;
    PORT
      LAYER metal3 ;
      RECT 0.000 299.600 0.140 299.740 ;
    END
  END dout[57]
  PIN dout[58]
    DIRECTION OUTPUT ;
    USE SIGNAL ;
    SHAPE ABUTMENT ;
    PORT
      LAYER metal3 ;
      RECT 0.000 301.000 0.140 301.140 ;
    END
  END dout[58]
  PIN dout[59]
    DIRECTION OUTPUT ;
    USE SIGNAL ;
    SHAPE ABUTMENT ;
    PORT
      LAYER metal3 ;
      RECT 0.000 302.400 0.140 302.540 ;
    END
  END dout[59]
  PIN dout[60]
    DIRECTION OUTPUT ;
    USE SIGNAL ;
    SHAPE ABUTMENT ;
    PORT
      LAYER metal3 ;
      RECT 0.000 303.800 0.140 303.940 ;
    END
  END dout[60]
  PIN dout[61]
    DIRECTION OUTPUT ;
    USE SIGNAL ;
    SHAPE ABUTMENT ;
    PORT
      LAYER metal3 ;
      RECT 0.000 305.200 0.140 305.340 ;
    END
  END dout[61]
  PIN dout[62]
    DIRECTION OUTPUT ;
    USE SIGNAL ;
    SHAPE ABUTMENT ;
    PORT
      LAYER metal3 ;
      RECT 0.000 306.600 0.140 306.740 ;
    END
  END dout[62]
  PIN dout[63]
    DIRECTION OUTPUT ;
    USE SIGNAL ;
    SHAPE ABUTMENT ;
    PORT
      LAYER metal3 ;
      RECT 0.000 308.000 0.140 308.140 ;
    END
  END dout[63]
  PIN dout[64]
    DIRECTION OUTPUT ;
    USE SIGNAL ;
    SHAPE ABUTMENT ;
    PORT
      LAYER metal3 ;
      RECT 0.000 309.400 0.140 309.540 ;
    END
  END dout[64]
  PIN dout[65]
    DIRECTION OUTPUT ;
    USE SIGNAL ;
    SHAPE ABUTMENT ;
    PORT
      LAYER metal3 ;
      RECT 0.000 310.800 0.140 310.940 ;
    END
  END dout[65]
  PIN dout[66]
    DIRECTION OUTPUT ;
    USE SIGNAL ;
    SHAPE ABUTMENT ;
    PORT
      LAYER metal3 ;
      RECT 0.000 312.200 0.140 312.340 ;
    END
  END dout[66]
  PIN dout[67]
    DIRECTION OUTPUT ;
    USE SIGNAL ;
    SHAPE ABUTMENT ;
    PORT
      LAYER metal3 ;
      RECT 0.000 313.600 0.140 313.740 ;
    END
  END dout[67]
  PIN dout[68]
    DIRECTION OUTPUT ;
    USE SIGNAL ;
    SHAPE ABUTMENT ;
    PORT
      LAYER metal3 ;
      RECT 0.000 315.000 0.140 315.140 ;
    END
  END dout[68]
  PIN dout[69]
    DIRECTION OUTPUT ;
    USE SIGNAL ;
    SHAPE ABUTMENT ;
    PORT
      LAYER metal3 ;
      RECT 0.000 316.400 0.140 316.540 ;
    END
  END dout[69]
  PIN dout[70]
    DIRECTION OUTPUT ;
    USE SIGNAL ;
    SHAPE ABUTMENT ;
    PORT
      LAYER metal3 ;
      RECT 0.000 317.800 0.140 317.940 ;
    END
  END dout[70]
  PIN dout[71]
    DIRECTION OUTPUT ;
    USE SIGNAL ;
    SHAPE ABUTMENT ;
    PORT
      LAYER metal3 ;
      RECT 0.000 319.200 0.140 319.340 ;
    END
  END dout[71]
  PIN dout[72]
    DIRECTION OUTPUT ;
    USE SIGNAL ;
    SHAPE ABUTMENT ;
    PORT
      LAYER metal3 ;
      RECT 0.000 320.600 0.140 320.740 ;
    END
  END dout[72]
  PIN dout[73]
    DIRECTION OUTPUT ;
    USE SIGNAL ;
    SHAPE ABUTMENT ;
    PORT
      LAYER metal3 ;
      RECT 0.000 322.000 0.140 322.140 ;
    END
  END dout[73]
  PIN dout[74]
    DIRECTION OUTPUT ;
    USE SIGNAL ;
    SHAPE ABUTMENT ;
    PORT
      LAYER metal3 ;
      RECT 0.000 323.400 0.140 323.540 ;
    END
  END dout[74]
  PIN dout[75]
    DIRECTION OUTPUT ;
    USE SIGNAL ;
    SHAPE ABUTMENT ;
    PORT
      LAYER metal3 ;
      RECT 0.000 324.800 0.140 324.940 ;
    END
  END dout[75]
  PIN dout[76]
    DIRECTION OUTPUT ;
    USE SIGNAL ;
    SHAPE ABUTMENT ;
    PORT
      LAYER metal3 ;
      RECT 0.000 326.200 0.140 326.340 ;
    END
  END dout[76]
  PIN dout[77]
    DIRECTION OUTPUT ;
    USE SIGNAL ;
    SHAPE ABUTMENT ;
    PORT
      LAYER metal3 ;
      RECT 0.000 327.600 0.140 327.740 ;
    END
  END dout[77]
  PIN dout[78]
    DIRECTION OUTPUT ;
    USE SIGNAL ;
    SHAPE ABUTMENT ;
    PORT
      LAYER metal3 ;
      RECT 0.000 329.000 0.140 329.140 ;
    END
  END dout[78]
  PIN dout[79]
    DIRECTION OUTPUT ;
    USE SIGNAL ;
    SHAPE ABUTMENT ;
    PORT
      LAYER metal3 ;
      RECT 0.000 330.400 0.140 330.540 ;
    END
  END dout[79]
  PIN dout[80]
    DIRECTION OUTPUT ;
    USE SIGNAL ;
    SHAPE ABUTMENT ;
    PORT
      LAYER metal3 ;
      RECT 0.000 331.800 0.140 331.940 ;
    END
  END dout[80]
  PIN dout[81]
    DIRECTION OUTPUT ;
    USE SIGNAL ;
    SHAPE ABUTMENT ;
    PORT
      LAYER metal3 ;
      RECT 0.000 333.200 0.140 333.340 ;
    END
  END dout[81]
  PIN dout[82]
    DIRECTION OUTPUT ;
    USE SIGNAL ;
    SHAPE ABUTMENT ;
    PORT
      LAYER metal3 ;
      RECT 0.000 334.600 0.140 334.740 ;
    END
  END dout[82]
  PIN dout[83]
    DIRECTION OUTPUT ;
    USE SIGNAL ;
    SHAPE ABUTMENT ;
    PORT
      LAYER metal3 ;
      RECT 0.000 336.000 0.140 336.140 ;
    END
  END dout[83]
  PIN dout[84]
    DIRECTION OUTPUT ;
    USE SIGNAL ;
    SHAPE ABUTMENT ;
    PORT
      LAYER metal3 ;
      RECT 0.000 337.400 0.140 337.540 ;
    END
  END dout[84]
  PIN dout[85]
    DIRECTION OUTPUT ;
    USE SIGNAL ;
    SHAPE ABUTMENT ;
    PORT
      LAYER metal3 ;
      RECT 0.000 338.800 0.140 338.940 ;
    END
  END dout[85]
  PIN dout[86]
    DIRECTION OUTPUT ;
    USE SIGNAL ;
    SHAPE ABUTMENT ;
    PORT
      LAYER metal3 ;
      RECT 0.000 340.200 0.140 340.340 ;
    END
  END dout[86]
  PIN dout[87]
    DIRECTION OUTPUT ;
    USE SIGNAL ;
    SHAPE ABUTMENT ;
    PORT
      LAYER metal3 ;
      RECT 0.000 341.600 0.140 341.740 ;
    END
  END dout[87]
  PIN dout[88]
    DIRECTION OUTPUT ;
    USE SIGNAL ;
    SHAPE ABUTMENT ;
    PORT
      LAYER metal3 ;
      RECT 0.000 343.000 0.140 343.140 ;
    END
  END dout[88]
  PIN dout[89]
    DIRECTION OUTPUT ;
    USE SIGNAL ;
    SHAPE ABUTMENT ;
    PORT
      LAYER metal3 ;
      RECT 0.000 344.400 0.140 344.540 ;
    END
  END dout[89]
  PIN dout[90]
    DIRECTION OUTPUT ;
    USE SIGNAL ;
    SHAPE ABUTMENT ;
    PORT
      LAYER metal3 ;
      RECT 0.000 345.800 0.140 345.940 ;
    END
  END dout[90]
  PIN dout[91]
    DIRECTION OUTPUT ;
    USE SIGNAL ;
    SHAPE ABUTMENT ;
    PORT
      LAYER metal3 ;
      RECT 0.000 347.200 0.140 347.340 ;
    END
  END dout[91]
  PIN dout[92]
    DIRECTION OUTPUT ;
    USE SIGNAL ;
    SHAPE ABUTMENT ;
    PORT
      LAYER metal3 ;
      RECT 0.000 348.600 0.140 348.740 ;
    END
  END dout[92]
  PIN dout[93]
    DIRECTION OUTPUT ;
    USE SIGNAL ;
    SHAPE ABUTMENT ;
    PORT
      LAYER metal3 ;
      RECT 0.000 350.000 0.140 350.140 ;
    END
  END dout[93]
  PIN dout[94]
    DIRECTION OUTPUT ;
    USE SIGNAL ;
    SHAPE ABUTMENT ;
    PORT
      LAYER metal3 ;
      RECT 0.000 351.400 0.140 351.540 ;
    END
  END dout[94]
  PIN dout[95]
    DIRECTION OUTPUT ;
    USE SIGNAL ;
    SHAPE ABUTMENT ;
    PORT
      LAYER metal3 ;
      RECT 0.000 352.800 0.140 352.940 ;
    END
  END dout[95]
  PIN dout[96]
    DIRECTION OUTPUT ;
    USE SIGNAL ;
    SHAPE ABUTMENT ;
    PORT
      LAYER metal3 ;
      RECT 0.000 354.200 0.140 354.340 ;
    END
  END dout[96]
  PIN dout[97]
    DIRECTION OUTPUT ;
    USE SIGNAL ;
    SHAPE ABUTMENT ;
    PORT
      LAYER metal3 ;
      RECT 0.000 355.600 0.140 355.740 ;
    END
  END dout[97]
  PIN dout[98]
    DIRECTION OUTPUT ;
    USE SIGNAL ;
    SHAPE ABUTMENT ;
    PORT
      LAYER metal3 ;
      RECT 0.000 357.000 0.140 357.140 ;
    END
  END dout[98]
  PIN dout[99]
    DIRECTION OUTPUT ;
    USE SIGNAL ;
    SHAPE ABUTMENT ;
    PORT
      LAYER metal3 ;
      RECT 0.000 358.400 0.140 358.540 ;
    END
  END dout[99]
  PIN dout[100]
    DIRECTION OUTPUT ;
    USE SIGNAL ;
    SHAPE ABUTMENT ;
    PORT
      LAYER metal3 ;
      RECT 0.000 359.800 0.140 359.940 ;
    END
  END dout[100]
  PIN dout[101]
    DIRECTION OUTPUT ;
    USE SIGNAL ;
    SHAPE ABUTMENT ;
    PORT
      LAYER metal3 ;
      RECT 0.000 361.200 0.140 361.340 ;
    END
  END dout[101]
  PIN dout[102]
    DIRECTION OUTPUT ;
    USE SIGNAL ;
    SHAPE ABUTMENT ;
    PORT
      LAYER metal3 ;
      RECT 0.000 362.600 0.140 362.740 ;
    END
  END dout[102]
  PIN dout[103]
    DIRECTION OUTPUT ;
    USE SIGNAL ;
    SHAPE ABUTMENT ;
    PORT
      LAYER metal3 ;
      RECT 0.000 364.000 0.140 364.140 ;
    END
  END dout[103]
  PIN dout[104]
    DIRECTION OUTPUT ;
    USE SIGNAL ;
    SHAPE ABUTMENT ;
    PORT
      LAYER metal3 ;
      RECT 0.000 365.400 0.140 365.540 ;
    END
  END dout[104]
  PIN dout[105]
    DIRECTION OUTPUT ;
    USE SIGNAL ;
    SHAPE ABUTMENT ;
    PORT
      LAYER metal3 ;
      RECT 0.000 366.800 0.140 366.940 ;
    END
  END dout[105]
  PIN dout[106]
    DIRECTION OUTPUT ;
    USE SIGNAL ;
    SHAPE ABUTMENT ;
    PORT
      LAYER metal3 ;
      RECT 0.000 368.200 0.140 368.340 ;
    END
  END dout[106]
  PIN dout[107]
    DIRECTION OUTPUT ;
    USE SIGNAL ;
    SHAPE ABUTMENT ;
    PORT
      LAYER metal3 ;
      RECT 0.000 369.600 0.140 369.740 ;
    END
  END dout[107]
  PIN dout[108]
    DIRECTION OUTPUT ;
    USE SIGNAL ;
    SHAPE ABUTMENT ;
    PORT
      LAYER metal3 ;
      RECT 0.000 371.000 0.140 371.140 ;
    END
  END dout[108]
  PIN dout[109]
    DIRECTION OUTPUT ;
    USE SIGNAL ;
    SHAPE ABUTMENT ;
    PORT
      LAYER metal3 ;
      RECT 0.000 372.400 0.140 372.540 ;
    END
  END dout[109]
  PIN dout[110]
    DIRECTION OUTPUT ;
    USE SIGNAL ;
    SHAPE ABUTMENT ;
    PORT
      LAYER metal3 ;
      RECT 0.000 373.800 0.140 373.940 ;
    END
  END dout[110]
  PIN dout[111]
    DIRECTION OUTPUT ;
    USE SIGNAL ;
    SHAPE ABUTMENT ;
    PORT
      LAYER metal3 ;
      RECT 0.000 375.200 0.140 375.340 ;
    END
  END dout[111]
  PIN dout[112]
    DIRECTION OUTPUT ;
    USE SIGNAL ;
    SHAPE ABUTMENT ;
    PORT
      LAYER metal3 ;
      RECT 0.000 376.600 0.140 376.740 ;
    END
  END dout[112]
  PIN dout[113]
    DIRECTION OUTPUT ;
    USE SIGNAL ;
    SHAPE ABUTMENT ;
    PORT
      LAYER metal3 ;
      RECT 0.000 378.000 0.140 378.140 ;
    END
  END dout[113]
  PIN dout[114]
    DIRECTION OUTPUT ;
    USE SIGNAL ;
    SHAPE ABUTMENT ;
    PORT
      LAYER metal3 ;
      RECT 0.000 379.400 0.140 379.540 ;
    END
  END dout[114]
  PIN dout[115]
    DIRECTION OUTPUT ;
    USE SIGNAL ;
    SHAPE ABUTMENT ;
    PORT
      LAYER metal3 ;
      RECT 0.000 380.800 0.140 380.940 ;
    END
  END dout[115]
  PIN dout[116]
    DIRECTION OUTPUT ;
    USE SIGNAL ;
    SHAPE ABUTMENT ;
    PORT
      LAYER metal3 ;
      RECT 0.000 382.200 0.140 382.340 ;
    END
  END dout[116]
  PIN dout[117]
    DIRECTION OUTPUT ;
    USE SIGNAL ;
    SHAPE ABUTMENT ;
    PORT
      LAYER metal3 ;
      RECT 0.000 383.600 0.140 383.740 ;
    END
  END dout[117]
  PIN dout[118]
    DIRECTION OUTPUT ;
    USE SIGNAL ;
    SHAPE ABUTMENT ;
    PORT
      LAYER metal3 ;
      RECT 0.000 385.000 0.140 385.140 ;
    END
  END dout[118]
  PIN dout[119]
    DIRECTION OUTPUT ;
    USE SIGNAL ;
    SHAPE ABUTMENT ;
    PORT
      LAYER metal3 ;
      RECT 0.000 386.400 0.140 386.540 ;
    END
  END dout[119]
  PIN dout[120]
    DIRECTION OUTPUT ;
    USE SIGNAL ;
    SHAPE ABUTMENT ;
    PORT
      LAYER metal3 ;
      RECT 0.000 387.800 0.140 387.940 ;
    END
  END dout[120]
  PIN dout[121]
    DIRECTION OUTPUT ;
    USE SIGNAL ;
    SHAPE ABUTMENT ;
    PORT
      LAYER metal3 ;
      RECT 0.000 389.200 0.140 389.340 ;
    END
  END dout[121]
  PIN dout[122]
    DIRECTION OUTPUT ;
    USE SIGNAL ;
    SHAPE ABUTMENT ;
    PORT
      LAYER metal3 ;
      RECT 0.000 390.600 0.140 390.740 ;
    END
  END dout[122]
  PIN dout[123]
    DIRECTION OUTPUT ;
    USE SIGNAL ;
    SHAPE ABUTMENT ;
    PORT
      LAYER metal3 ;
      RECT 0.000 392.000 0.140 392.140 ;
    END
  END dout[123]
  PIN dout[124]
    DIRECTION OUTPUT ;
    USE SIGNAL ;
    SHAPE ABUTMENT ;
    PORT
      LAYER metal3 ;
      RECT 0.000 393.400 0.140 393.540 ;
    END
  END dout[124]
  PIN dout[125]
    DIRECTION OUTPUT ;
    USE SIGNAL ;
    SHAPE ABUTMENT ;
    PORT
      LAYER metal3 ;
      RECT 0.000 394.800 0.140 394.940 ;
    END
  END dout[125]
  PIN dout[126]
    DIRECTION OUTPUT ;
    USE SIGNAL ;
    SHAPE ABUTMENT ;
    PORT
      LAYER metal3 ;
      RECT 0.000 396.200 0.140 396.340 ;
    END
  END dout[126]
  PIN dout[127]
    DIRECTION OUTPUT ;
    USE SIGNAL ;
    SHAPE ABUTMENT ;
    PORT
      LAYER metal3 ;
      RECT 0.000 397.600 0.140 397.740 ;
    END
  END dout[127]
  PIN dout[128]
    DIRECTION OUTPUT ;
    USE SIGNAL ;
    SHAPE ABUTMENT ;
    PORT
      LAYER metal3 ;
      RECT 0.000 399.000 0.140 399.140 ;
    END
  END dout[128]
  PIN dout[129]
    DIRECTION OUTPUT ;
    USE SIGNAL ;
    SHAPE ABUTMENT ;
    PORT
      LAYER metal3 ;
      RECT 0.000 400.400 0.140 400.540 ;
    END
  END dout[129]
  PIN dout[130]
    DIRECTION OUTPUT ;
    USE SIGNAL ;
    SHAPE ABUTMENT ;
    PORT
      LAYER metal3 ;
      RECT 0.000 401.800 0.140 401.940 ;
    END
  END dout[130]
  PIN dout[131]
    DIRECTION OUTPUT ;
    USE SIGNAL ;
    SHAPE ABUTMENT ;
    PORT
      LAYER metal3 ;
      RECT 0.000 403.200 0.140 403.340 ;
    END
  END dout[131]
  PIN dout[132]
    DIRECTION OUTPUT ;
    USE SIGNAL ;
    SHAPE ABUTMENT ;
    PORT
      LAYER metal3 ;
      RECT 0.000 404.600 0.140 404.740 ;
    END
  END dout[132]
  PIN dout[133]
    DIRECTION OUTPUT ;
    USE SIGNAL ;
    SHAPE ABUTMENT ;
    PORT
      LAYER metal3 ;
      RECT 0.000 406.000 0.140 406.140 ;
    END
  END dout[133]
  PIN dout[134]
    DIRECTION OUTPUT ;
    USE SIGNAL ;
    SHAPE ABUTMENT ;
    PORT
      LAYER metal3 ;
      RECT 0.000 407.400 0.140 407.540 ;
    END
  END dout[134]
  PIN dout[135]
    DIRECTION OUTPUT ;
    USE SIGNAL ;
    SHAPE ABUTMENT ;
    PORT
      LAYER metal3 ;
      RECT 0.000 408.800 0.140 408.940 ;
    END
  END dout[135]
  PIN dout[136]
    DIRECTION OUTPUT ;
    USE SIGNAL ;
    SHAPE ABUTMENT ;
    PORT
      LAYER metal3 ;
      RECT 0.000 410.200 0.140 410.340 ;
    END
  END dout[136]
  PIN dout[137]
    DIRECTION OUTPUT ;
    USE SIGNAL ;
    SHAPE ABUTMENT ;
    PORT
      LAYER metal3 ;
      RECT 0.000 411.600 0.140 411.740 ;
    END
  END dout[137]
  PIN dout[138]
    DIRECTION OUTPUT ;
    USE SIGNAL ;
    SHAPE ABUTMENT ;
    PORT
      LAYER metal3 ;
      RECT 0.000 413.000 0.140 413.140 ;
    END
  END dout[138]
  PIN dout[139]
    DIRECTION OUTPUT ;
    USE SIGNAL ;
    SHAPE ABUTMENT ;
    PORT
      LAYER metal3 ;
      RECT 0.000 414.400 0.140 414.540 ;
    END
  END dout[139]
  PIN dout[140]
    DIRECTION OUTPUT ;
    USE SIGNAL ;
    SHAPE ABUTMENT ;
    PORT
      LAYER metal3 ;
      RECT 0.000 415.800 0.140 415.940 ;
    END
  END dout[140]
  PIN dout[141]
    DIRECTION OUTPUT ;
    USE SIGNAL ;
    SHAPE ABUTMENT ;
    PORT
      LAYER metal3 ;
      RECT 0.000 417.200 0.140 417.340 ;
    END
  END dout[141]
  PIN dout[142]
    DIRECTION OUTPUT ;
    USE SIGNAL ;
    SHAPE ABUTMENT ;
    PORT
      LAYER metal3 ;
      RECT 0.000 418.600 0.140 418.740 ;
    END
  END dout[142]
  PIN dout[143]
    DIRECTION OUTPUT ;
    USE SIGNAL ;
    SHAPE ABUTMENT ;
    PORT
      LAYER metal3 ;
      RECT 0.000 420.000 0.140 420.140 ;
    END
  END dout[143]
  PIN VSS
    DIRECTION INOUT ;
    USE GROUND ;
    SHAPE ABUTMENT ;
    PORT
      LAYER metal3 ;
      RECT 0.000 421.400 374.300 421.540 ;
    END
  END VSS
  PIN VDD
    DIRECTION INOUT ;
    USE POWER ;
    SHAPE ABUTMENT ;
    PORT
      LAYER metal3 ;
      RECT 0.000 422.800 374.300 422.940 ;
    END
  END VDD
  OBS
    LAYER metal1 ;
      RECT 0.000 0.000 374.300 749.000 ;
    LAYER metal2 ;
      RECT 0.000 0.000 374.300 749.000 ;
    LAYER metal3 ;
      RECT 0.000 0.000 374.300 749.000 ;
    LAYER metal4 ;
      RECT 0.000 0.000 374.300 749.000 ;
  END
END icache_data_ram
END LIBRARY
